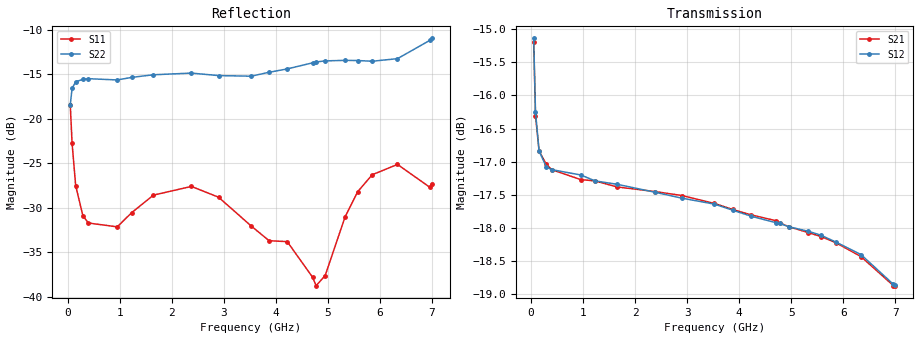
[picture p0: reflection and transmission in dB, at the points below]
! Integrated Device Technology
! Corporate Headquarters
! 6024 Silver Creek Valley Road
! San Jose, CA 95138  USA
! Phone:  1-408-284-8200
! Toll Free:  1-800-223-1366
! Webpage:  http://www.idt.com/
! Timing and RF Division
! 515 Groton Road, Suite 102
! Westford, MA 01886-6024
! Device:  F2258
! Description: Voltage Variable RF Attenuator
! Frequency:  50.0 -  6000.00 MHz
! Package:  3x3 mm Thin QFN Plastic Package: 16 pin
! Ports:  2 RF, 2 DC
!  Pin  1  = NC
!  Pin  2  = NC
!  Pin  3  = RF2  = Port 2
!  Pin  4  = GND
!  Pin  5  = Vdd
!  Pin  6  = NC
!  Pin  7  = VCTRL
!  Pin  8  = NC
!  Pin  9  = GND
!  Pin 10  = RF1  = Port 1
!  Pin 11  = NC
!  Pin 12  = NC
!  Pin 13  = NC
!  Pin 14  = NC
!  Pin 15  = NC
!  Pin 16  = NC
! Vcntrl:  1.240 Volts
! Vdd:  +3.300 Volts
! Current:  1.161 mA
! Data:  The device was measured on a the F2258 evaluation board which has
!  individual transmission lines to the RF pins.  Data was collected
!  using a calibrated network analyzer.  The evaluation board was
!  de-embedded using a TRL calibration technique.
!  The reference plane is the edge of the package pin.
! Misc:  SN 10
!  Action Tracker AT0285
! Date Measured:  2014-12-10
! Date:  2016-01-13  MJV
! Note:
!  Integrated Device Technology supplies this data as a sample of measured
!  data at the package pin for this product.  Your particular data for this
!  product may vary.
!  Data was taken at 25 degrees C.
!  Integrated Device Technology reserves the right to change this data at anytime.
!Freq_(GHz)  S11M_(dB)  S11P_(deg)  S21M_(dB)  S21P_(deg)  S12M_(dB)  S12P_(deg)  S22M_(dB)  S22P_(deg)
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# GHz S dB R 50
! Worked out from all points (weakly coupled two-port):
!   201 points, 50 MHz to 7 GHz, reference 50 ohm
!   highest |S21| = -15.19 dB at 50 MHz (marker M1); lowest = -18.9 dB at 6.965 GHz (marker M2)
!   lowest |S11| = -38.8 dB at 4.776 GHz (marker M3), VSWR 1.02, Z = 50.5 + j1.04 ohm
!   |S11| at or under -10 dB: start of sweep to end of sweep
!   |S22| runs from -18.4 to -11.0 dB; largest |S21 - S12| = 0.0011
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0.05  -18.45 -97.5  -15.19 -25.5  -15.14 -25.5  -18.45 -25.8
0.08475  -22.75 -85.5  -16.31 -18.1  -16.25 -18.1  -16.59 -12.9
0.15425  -27.53 -67.6  -16.84 -12.3  -16.84 -12.3  -15.84 -9.6
0.29325  -30.90 -43.2  -17.04 -9.9  -17.08 -9.9  -15.57 -10.6
0.3975  -31.71 -33.3  -17.12 -10.1  -17.12 -10.1  -15.50 -12.4
0.9535  -32.14 -21.2  -17.27 -15.9  -17.20 -15.9  -15.64 -26.4
1.2315  -30.54 -13.0  -17.29 -19.5  -17.29 -19.5  -15.35 -33.4
1.6485  -28.58 -6.7  -17.38 -25.1  -17.34 -25.1  -15.06 -43.1
2.37825  -27.60 7.7  -17.45 -35.0  -17.46 -35.0  -14.87 -59.7
2.8995  -28.81 23.4  -17.51 -42.3  -17.55 -42.3  -15.15 -74.1
3.525  -32.03 55.3  -17.63 -51.2  -17.64 -51.2  -15.22 -97.3
3.8725  -33.70 80.9  -17.72 -56.1  -17.73 -56.1  -14.78 -110.4
4.22  -33.80 93.5  -17.80 -61.0  -17.82 -60.9  -14.40 -120.6
4.7065  -37.79 72.8  -17.89 -67.7  -17.92 -67.6  -13.72 -130.7
4.776  -38.75 63.2  -17.92 -68.7  -17.93 -68.6  -13.62 -131.8
4.94975  -37.61 31.2  -17.98 -71.0  -17.98 -71.0  -13.50 -134.1
5.332  -31.03 2.8  -18.07 -76.2  -18.05 -76.2  -13.44 -138.7
5.57525  -28.19 0.5  -18.13 -79.4  -18.11 -79.5  -13.46 -142.5
5.85325  -26.29 3.4  -18.22 -83.2  -18.21 -83.3  -13.54 -147.2
6.33975  -25.13 15.3  -18.43 -90.0  -18.40 -90.1  -13.25 -159.5
6.96525  -27.71 78.6  -18.87 -97.4  -18.85 -97.3  -11.18 -178.4
7  -27.32 85.4  -18.87 -97.6  -18.86 -97.7  -10.97 -179.5
